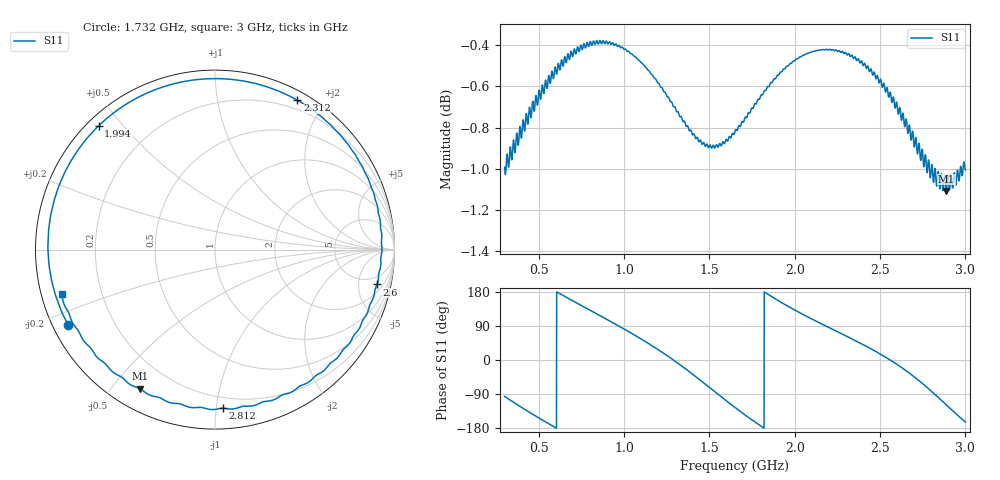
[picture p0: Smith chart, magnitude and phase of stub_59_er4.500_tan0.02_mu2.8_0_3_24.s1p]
! Chirptenna · simulación 3D de un stub abierto
# HZ S RI R 50
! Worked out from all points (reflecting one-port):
!   2001 points, 300 MHz to 3 GHz, reference 50 ohm
!   lowest |S11| = -1.1 dB at 2.888 GHz (marker M1), VSWR 15.70, Z = 4.31 - j29.7 ohm
!   phase of S11 starts at -96 deg and turns -787 deg over the sweep
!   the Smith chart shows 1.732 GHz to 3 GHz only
!   S11 on the Smith chart (normalised r, x): 1.732 GHz: 0.04, -0.24; 1.994 GHz: 0.03, +0.43; 2.312 GHz: 0.10, +1.69; 2.6 GHz: 3.12, -8.23; 2.812 GHz: 0.13, -1.04; 3 GHz: 0.06, -0.14
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3e8  -0.099 -0.8865
3.7965e8  -0.4441 -0.7863
4.7685e8  -0.7674 -0.5116
6.375e8  -0.9356 0.1395
7.185e8  -0.8352 0.4537
8.1705e8  -0.5804 0.7603
9.75e8  0.0305 0.954
1.13025e9  0.6407 0.692
1.22745e9  0.8804 0.3046
1.3125e9  0.9125 -0.1192
1.3989e9  0.7311 -0.5397
1.4961e9  0.2986 -0.851
1.57035e9  -0.1149 -0.8956
1.65e9  -0.5263 -0.7426
1.73235e9  -0.8189 -0.4186
1.8498e9  -0.923 0.1388
1.9875e9  -0.6681 0.6702
1.99425e9  -0.6483 0.6898
2.15085e9  -0.1108 0.9461
2.3115e9  0.4594 0.8318
2.325e9  0.5027 0.805
2.47755e9  0.8697 0.3497
2.6004e9  0.9027 -0.1944
2.6625e9  0.7737 -0.4775
2.7408e9  0.4602 -0.7696
2.81235e9  0.0424 -0.8835
2.88795e9  -0.4182 -0.7746
3e9  -0.8552 -0.249
